VERSION 5.8 ;
BUSBITCHARS "[]" ;
DIVIDERCHAR "/" ;
CLEARANCEMEASURE EUCLIDEAN ;

SITE coresite_DH_P
    SIZE 0.0450 BY 0.2880 ;
    CLASS CORE ;
    SYMMETRY X Y ;
END coresite_DH_P

SITE coresite_DH_N
    SIZE 0.0450 BY 0.2880 ;
    CLASS CORE ;
    SYMMETRY X Y ;
END coresite_DH_N

SITE coresite
    SIZE 0.0450 BY 0.1440 ;
    CLASS CORE ;
    SYMMETRY X Y ;
END coresite

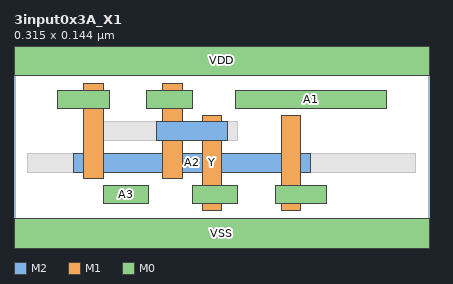
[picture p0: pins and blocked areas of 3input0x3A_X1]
MACRO 3input0x3A_X1
  CLASS CORE ;
  ORIGIN 0 0 ;
  FOREIGN 3input0x3A_X1 0 0 ;
  SIZE 0.3150 BY 0.1440 ;
  SYMMETRY X Y ;
  SITE coresite ;
  PIN A2
    DIRECTION INPUT ;
    USE SIGNAL ;
    PORT
      LAYER M2 ;
        RECT 0.0450 0.0670 0.2250 0.0530 ;
      LAYER M1 ;
        RECT 0.2025 0.0960 0.2175 0.0240 ;
        RECT 0.0525 0.1200 0.0675 0.0480 ;
      LAYER M0 ;
        RECT 0.1980 0.0430 0.2370 0.0290 ;
        RECT 0.0330 0.1150 0.0720 0.1010 ;
    END
  END A2
  PIN Y
    DIRECTION OUTPUT ;
    USE SIGNAL ;
    PORT
      LAYER M2 ;
        RECT 0.1080 0.0910 0.1620 0.0770 ;
      LAYER M1 ;
        RECT 0.1425 0.0960 0.1575 0.0240 ;
        RECT 0.1125 0.1200 0.1275 0.0480 ;
      LAYER M0 ;
        RECT 0.1350 0.0430 0.1695 0.0290 ;
        RECT 0.1005 0.1150 0.1350 0.1010 ;
    END
  END Y
  PIN A3
    DIRECTION INPUT ;
    USE SIGNAL ;
    PORT
      LAYER M0 ;
        RECT 0.0675 0.0430 0.1020 0.0290 ;
    END
  END A3
  PIN A1
    DIRECTION INPUT ;
    USE SIGNAL ;
    PORT
      LAYER M0 ;
        RECT 0.1680 0.1150 0.2820 0.1010 ;
    END
  END A1
  PIN VDD
    DIRECTION INOUT ;
    USE POWER ;
    SHAPE ABUTMENT ;
    PORT
      LAYER M0 ;
        RECT 0.0000 0.1260 0.3150 0.1620 ;
    END
  END VDD
  PIN VSS
    DIRECTION INOUT ;
    USE GROUND ;
    SHAPE ABUTMENT ;
    PORT
      LAYER M0 ;
        RECT 0.0000 -0.0180 0.3150 0.0180 ;
    END
  END VSS
  OBS
      LAYER V1 ;
        RECT 0.1130 0.0770 0.1270 0.0910 ;
        RECT 0.1430 0.0770 0.1570 0.0910 ;
        RECT 0.0530 0.0530 0.0670 0.0670 ;
        RECT 0.2030 0.0530 0.2170 0.0670 ;
      LAYER V0 ;
        RECT 0.1130 0.1010 0.1270 0.1150 ;
        RECT 0.1430 0.0290 0.1570 0.0430 ;
        RECT 0.0530 0.1010 0.0670 0.1150 ;
        RECT 0.2030 0.0290 0.2170 0.0430 ;
      LAYER M0 ;
        RECT 0.0105 0.0530 0.3045 0.0670 ;
        RECT 0.0555 0.0770 0.1695 0.0910 ;
  END
END 3input0x3A_X1

END LIBRARY
